VERSION 5.7 ;
  NOWIREEXTENSIONATPIN ON ;
  DIVIDERCHAR "/" ;
  BUSBITCHARS "[]" ;
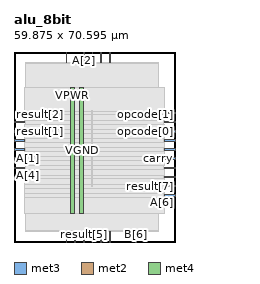
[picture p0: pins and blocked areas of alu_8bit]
MACRO alu_8bit
  CLASS BLOCK ;
  FOREIGN alu_8bit ;
  ORIGIN 0.000 0.000 ;
  SIZE 59.875 BY 70.595 ;
  PIN A[0]
    DIRECTION INPUT ;
    USE SIGNAL ;
    ANTENNAGATEAREA 0.126000 ;
    PORT
      LAYER met3 ;
        RECT 55.875 34.040 59.875 34.640 ;
    END
  END A[0]
  PIN A[1]
    DIRECTION INPUT ;
    USE SIGNAL ;
    ANTENNAGATEAREA 0.213000 ;
    PORT
      LAYER met3 ;
        RECT 0.000 30.640 4.000 31.240 ;
    END
  END A[1]
  PIN A[2]
    DIRECTION INPUT ;
    USE SIGNAL ;
    ANTENNAGATEAREA 0.213000 ;
    PORT
      LAYER met2 ;
        RECT 25.850 66.595 26.130 70.595 ;
    END
  END A[2]
  PIN A[3]
    DIRECTION INPUT ;
    USE SIGNAL ;
    ANTENNAGATEAREA 0.159000 ;
    PORT
      LAYER met2 ;
        RECT 32.290 66.595 32.570 70.595 ;
    END
  END A[3]
  PIN A[4]
    DIRECTION INPUT ;
    USE SIGNAL ;
    ANTENNAGATEAREA 0.213000 ;
    PORT
      LAYER met3 ;
        RECT 0.000 27.240 4.000 27.840 ;
    END
  END A[4]
  PIN A[5]
    DIRECTION INPUT ;
    USE SIGNAL ;
    ANTENNAGATEAREA 0.213000 ;
    PORT
      LAYER met2 ;
        RECT 22.630 0.000 22.910 4.000 ;
    END
  END A[5]
  PIN A[6]
    DIRECTION INPUT ;
    USE SIGNAL ;
    ANTENNAGATEAREA 0.196500 ;
    PORT
      LAYER met3 ;
        RECT 55.875 17.040 59.875 17.640 ;
    END
  END A[6]
  PIN A[7]
    DIRECTION INPUT ;
    USE SIGNAL ;
    ANTENNAGATEAREA 0.196500 ;
    PORT
      LAYER met3 ;
        RECT 55.875 23.840 59.875 24.440 ;
    END
  END A[7]
  PIN B[0]
    DIRECTION INPUT ;
    USE SIGNAL ;
    ANTENNAGATEAREA 0.196500 ;
    PORT
      LAYER met3 ;
        RECT 55.875 37.440 59.875 38.040 ;
    END
  END B[0]
  PIN B[1]
    DIRECTION INPUT ;
    USE SIGNAL ;
    ANTENNAGATEAREA 0.126000 ;
    PORT
      LAYER met3 ;
        RECT 0.000 34.040 4.000 34.640 ;
    END
  END B[1]
  PIN B[2]
    DIRECTION INPUT ;
    USE SIGNAL ;
    ANTENNAGATEAREA 0.196500 ;
    PORT
      LAYER met2 ;
        RECT 19.410 66.595 19.690 70.595 ;
    END
  END B[2]
  PIN B[3]
    DIRECTION INPUT ;
    USE SIGNAL ;
    ANTENNAGATEAREA 0.126000 ;
    PORT
      LAYER met2 ;
        RECT 35.510 66.595 35.790 70.595 ;
    END
  END B[3]
  PIN B[4]
    DIRECTION INPUT ;
    USE SIGNAL ;
    ANTENNAGATEAREA 0.196500 ;
    PORT
      LAYER met3 ;
        RECT 0.000 23.840 4.000 24.440 ;
    END
  END B[4]
  PIN B[5]
    DIRECTION INPUT ;
    USE SIGNAL ;
    ANTENNAGATEAREA 0.196500 ;
    PORT
      LAYER met2 ;
        RECT 19.410 0.000 19.690 4.000 ;
    END
  END B[5]
  PIN B[6]
    DIRECTION INPUT ;
    USE SIGNAL ;
    ANTENNAGATEAREA 0.196500 ;
    PORT
      LAYER met2 ;
        RECT 45.170 0.000 45.450 4.000 ;
    END
  END B[6]
  PIN B[7]
    DIRECTION INPUT ;
    USE SIGNAL ;
    ANTENNAGATEAREA 0.196500 ;
    PORT
      LAYER met3 ;
        RECT 55.875 27.240 59.875 27.840 ;
    END
  END B[7]
  PIN VGND
    DIRECTION INOUT ;
    USE GROUND ;
    PORT
      LAYER met4 ;
        RECT 24.340 10.640 25.940 57.360 ;
    END
  END VGND
  PIN VPWR
    DIRECTION INOUT ;
    USE POWER ;
    PORT
      LAYER met4 ;
        RECT 21.040 10.640 22.640 57.360 ;
    END
  END VPWR
  PIN carry
    DIRECTION OUTPUT ;
    USE SIGNAL ;
    ANTENNADIFFAREA 0.445500 ;
    PORT
      LAYER met3 ;
        RECT 55.875 30.640 59.875 31.240 ;
    END
  END carry
  PIN opcode[0]
    DIRECTION INPUT ;
    USE SIGNAL ;
    ANTENNAGATEAREA 0.196500 ;
    PORT
      LAYER met3 ;
        RECT 55.875 40.840 59.875 41.440 ;
    END
  END opcode[0]
  PIN opcode[1]
    DIRECTION INPUT ;
    USE SIGNAL ;
    ANTENNAGATEAREA 0.196500 ;
    PORT
      LAYER met3 ;
        RECT 55.875 44.240 59.875 44.840 ;
    END
  END opcode[1]
  PIN opcode[2]
    DIRECTION INPUT ;
    USE SIGNAL ;
    ANTENNAGATEAREA 0.196500 ;
    PORT
      LAYER met3 ;
        RECT 55.875 47.640 59.875 48.240 ;
    END
  END opcode[2]
  PIN result[0]
    DIRECTION OUTPUT ;
    USE SIGNAL ;
    ANTENNADIFFAREA 0.445500 ;
    PORT
      LAYER met3 ;
        RECT 0.000 37.440 4.000 38.040 ;
    END
  END result[0]
  PIN result[1]
    DIRECTION OUTPUT ;
    USE SIGNAL ;
    ANTENNADIFFAREA 0.445500 ;
    PORT
      LAYER met3 ;
        RECT 0.000 40.840 4.000 41.440 ;
    END
  END result[1]
  PIN result[2]
    DIRECTION OUTPUT ;
    USE SIGNAL ;
    ANTENNADIFFAREA 0.445500 ;
    PORT
      LAYER met3 ;
        RECT 0.000 44.240 4.000 44.840 ;
    END
  END result[2]
  PIN result[3]
    DIRECTION OUTPUT ;
    USE SIGNAL ;
    ANTENNADIFFAREA 0.445500 ;
    PORT
      LAYER met2 ;
        RECT 29.070 66.595 29.350 70.595 ;
    END
  END result[3]
  PIN result[4]
    DIRECTION OUTPUT ;
    USE SIGNAL ;
    ANTENNADIFFAREA 0.445500 ;
    PORT
      LAYER met2 ;
        RECT 29.070 0.000 29.350 4.000 ;
    END
  END result[4]
  PIN result[5]
    DIRECTION OUTPUT ;
    USE SIGNAL ;
    ANTENNADIFFAREA 0.445500 ;
    PORT
      LAYER met2 ;
        RECT 25.850 0.000 26.130 4.000 ;
    END
  END result[5]
  PIN result[6]
    DIRECTION OUTPUT ;
    USE SIGNAL ;
    ANTENNADIFFAREA 0.445500 ;
    PORT
      LAYER met2 ;
        RECT 32.290 0.000 32.570 4.000 ;
    END
  END result[6]
  PIN result[7]
    DIRECTION OUTPUT ;
    USE SIGNAL ;
    ANTENNADIFFAREA 0.445500 ;
    PORT
      LAYER met3 ;
        RECT 55.875 20.440 59.875 21.040 ;
    END
  END result[7]
  PIN zero
    DIRECTION OUTPUT ;
    USE SIGNAL ;
    ANTENNADIFFAREA 0.445500 ;
    PORT
      LAYER met2 ;
        RECT 35.510 0.000 35.790 4.000 ;
    END
  END zero
  OBS
      LAYER nwell ;
        RECT 5.330 10.795 54.470 57.310 ;
      LAYER li1 ;
        RECT 5.520 10.795 54.280 57.205 ;
      LAYER met1 ;
        RECT 4.210 10.640 54.280 57.360 ;
      LAYER met2 ;
        RECT 4.230 66.315 19.130 66.595 ;
        RECT 19.970 66.315 25.570 66.595 ;
        RECT 26.410 66.315 28.790 66.595 ;
        RECT 29.630 66.315 32.010 66.595 ;
        RECT 32.850 66.315 35.230 66.595 ;
        RECT 36.070 66.315 53.720 66.595 ;
        RECT 4.230 4.280 53.720 66.315 ;
        RECT 4.230 4.000 19.130 4.280 ;
        RECT 19.970 4.000 22.350 4.280 ;
        RECT 23.190 4.000 25.570 4.280 ;
        RECT 26.410 4.000 28.790 4.280 ;
        RECT 29.630 4.000 32.010 4.280 ;
        RECT 32.850 4.000 35.230 4.280 ;
        RECT 36.070 4.000 44.890 4.280 ;
        RECT 45.730 4.000 53.720 4.280 ;
      LAYER met3 ;
        RECT 3.990 48.640 55.875 57.285 ;
        RECT 3.990 47.240 55.475 48.640 ;
        RECT 3.990 45.240 55.875 47.240 ;
        RECT 4.400 43.840 55.475 45.240 ;
        RECT 3.990 41.840 55.875 43.840 ;
        RECT 4.400 40.440 55.475 41.840 ;
        RECT 3.990 38.440 55.875 40.440 ;
        RECT 4.400 37.040 55.475 38.440 ;
        RECT 3.990 35.040 55.875 37.040 ;
        RECT 4.400 33.640 55.475 35.040 ;
        RECT 3.990 31.640 55.875 33.640 ;
        RECT 4.400 30.240 55.475 31.640 ;
        RECT 3.990 28.240 55.875 30.240 ;
        RECT 4.400 26.840 55.475 28.240 ;
        RECT 3.990 24.840 55.875 26.840 ;
        RECT 4.400 23.440 55.475 24.840 ;
        RECT 3.990 21.440 55.875 23.440 ;
        RECT 3.990 20.040 55.475 21.440 ;
        RECT 3.990 18.040 55.875 20.040 ;
        RECT 3.990 16.640 55.475 18.040 ;
        RECT 3.990 10.715 55.875 16.640 ;
      LAYER met4 ;
        RECT 28.815 20.575 29.145 48.785 ;
  END
END alu_8bit
END LIBRARY

